VERSION 5.8 ;
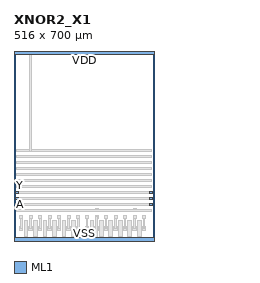
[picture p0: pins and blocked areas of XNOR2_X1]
MACRO XNOR2_X1
  CLASS CORE ;
  ORIGIN 0 0 ;
  SIZE 516 BY 700 ;
  SITE ICPS2023_5_ROW700 ;
  PIN A
    DIRECTION INPUT ;
    USE SIGNAL ;
    PORT
      LAYER ML1 ;
        RECT 5 130 15 140 ;
        RECT 501 130 511 140 ;
    END
  END A
  PIN B
    DIRECTION INPUT ;
    USE SIGNAL ;
    PORT
      LAYER ML1 ;
        RECT 5 152 15 162 ;
        RECT 501 152 511 162 ;
    END
  END B
  PIN Y
    DIRECTION OUTPUT ;
    USE SIGNAL ;
    PORT
      LAYER ML1 ;
        RECT 5 174 15 184 ;
        RECT 501 174 511 184 ;
    END
  END Y
  PIN VDD
    DIRECTION INOUT ;
    USE POWER ;
    PORT
      LAYER ML1 ;
        RECT 0 688 516 700 ;
    END
  END VDD
  PIN VSS
    DIRECTION INOUT ;
    USE GROUND ;
    PORT
      LAYER ML1 ;
        RECT 0 0 516 12 ;
    END
  END VSS
  OBS
    LAYER ML1 ;
      RECT 20 39.5 33 52.5 ;
      RECT 55 39.5 68 52.5 ;
      RECT 90 39.5 103 52.5 ;
      RECT 125 39.5 138 52.5 ;
      RECT 160 39.5 173 52.5 ;
      RECT 195 39.5 208 52.5 ;
      RECT 230 39.5 243 52.5 ;
      RECT 37.5 16 50.5 29 ;
      RECT 37.5 63 50.5 76 ;
      RECT 37 16 51 76 ;
      RECT 72.5 16 85.5 29 ;
      RECT 72.5 63 85.5 76 ;
      RECT 72 16 86 76 ;
      RECT 107.5 16 120.5 29 ;
      RECT 107.5 63 120.5 76 ;
      RECT 107 16 121 76 ;
      RECT 142.5 16 155.5 29 ;
      RECT 142.5 63 155.5 76 ;
      RECT 142 16 156 76 ;
      RECT 177.5 16 190.5 29 ;
      RECT 177.5 63 190.5 76 ;
      RECT 177 16 191 76 ;
      RECT 212.5 16 225.5 29 ;
      RECT 212.5 63 225.5 76 ;
      RECT 212 16 226 76 ;
      RECT 23.5 46 29.5 89 ;
      RECT 21.5 84 31.5 94 ;
      RECT 21.5 240 31.5 250 ;
      RECT 58.5 46 64.5 89 ;
      RECT 56.5 84 66.5 94 ;
      RECT 56.5 328 66.5 338 ;
      RECT 93.5 46 99.5 89 ;
      RECT 91.5 84 101.5 94 ;
      RECT 91.5 284 101.5 294 ;
      RECT 128.5 46 134.5 89 ;
      RECT 126.5 84 136.5 94 ;
      RECT 126.5 174 136.5 184 ;
      RECT 163.5 46 169.5 89 ;
      RECT 161.5 84 171.5 94 ;
      RECT 161.5 306 171.5 316 ;
      RECT 198.5 46 204.5 89 ;
      RECT 196.5 84 206.5 94 ;
      RECT 196.5 328 206.5 338 ;
      RECT 233.5 46 239.5 89 ;
      RECT 231.5 84 241.5 94 ;
      RECT 231.5 262 241.5 272 ;
      RECT 39 130 49 140 ;
      RECT 74 130 84 140 ;
      RECT 109 152 119 162 ;
      RECT 144 262 154 272 ;
      RECT 179 240 189 250 ;
      RECT 214 152 224 162 ;
      RECT 263 39.5 276 52.5 ;
      RECT 298 39.5 311 52.5 ;
      RECT 333 39.5 346 52.5 ;
      RECT 368 39.5 381 52.5 ;
      RECT 403 39.5 416 52.5 ;
      RECT 438 39.5 451 52.5 ;
      RECT 473 39.5 486 52.5 ;
      RECT 280.5 16 293.5 29 ;
      RECT 280.5 63 293.5 76 ;
      RECT 280 16 294 76 ;
      RECT 315.5 16 328.5 29 ;
      RECT 315.5 63 328.5 76 ;
      RECT 315 16 329 76 ;
      RECT 350.5 16 363.5 29 ;
      RECT 350.5 63 363.5 76 ;
      RECT 350 16 364 76 ;
      RECT 385.5 16 398.5 29 ;
      RECT 385.5 63 398.5 76 ;
      RECT 385 16 399 76 ;
      RECT 420.5 16 433.5 29 ;
      RECT 420.5 63 433.5 76 ;
      RECT 420 16 434 76 ;
      RECT 455.5 16 468.5 29 ;
      RECT 455.5 63 468.5 76 ;
      RECT 455 16 469 76 ;
      RECT 266.5 46 272.5 89 ;
      RECT 264.5 84 274.5 94 ;
      RECT 264.5 240 274.5 250 ;
      RECT 301.5 46 307.5 89 ;
      RECT 299.5 84 309.5 94 ;
      RECT 299.5 108 309.5 118 ;
      RECT 336.5 46 342.5 89 ;
      RECT 334.5 84 344.5 94 ;
      RECT 334.5 196 344.5 206 ;
      RECT 371.5 46 377.5 89 ;
      RECT 369.5 84 379.5 94 ;
      RECT 369.5 174 379.5 184 ;
      RECT 406.5 46 412.5 89 ;
      RECT 404.5 84 414.5 94 ;
      RECT 404.5 218 414.5 228 ;
      RECT 441.5 46 447.5 89 ;
      RECT 439.5 84 449.5 94 ;
      RECT 439.5 108 449.5 118 ;
      RECT 476.5 46 482.5 89 ;
      RECT 474.5 84 484.5 94 ;
      RECT 474.5 262 484.5 272 ;
      RECT 282 130 292 140 ;
      RECT 317 262 327 272 ;
      RECT 352 130 362 140 ;
      RECT 387 240 397 250 ;
      RECT 422 152 432 162 ;
      RECT 457 152 467 162 ;
      RECT 10 110 506 116 ;
      RECT 10 132 506 138 ;
      RECT 10 154 506 160 ;
      RECT 10 176 506 182 ;
      RECT 10 198 506 204 ;
      RECT 10 220 506 226 ;
      RECT 10 242 506 248 ;
      RECT 10 264 506 270 ;
      RECT 10 286 506 292 ;
      RECT 10 308 506 314 ;
      RECT 10 330 506 336 ;
      RECT 301.5 3 307.5 92 ;
      RECT 58.5 330 64.5 697 ;
  END
END XNOR2_X1
